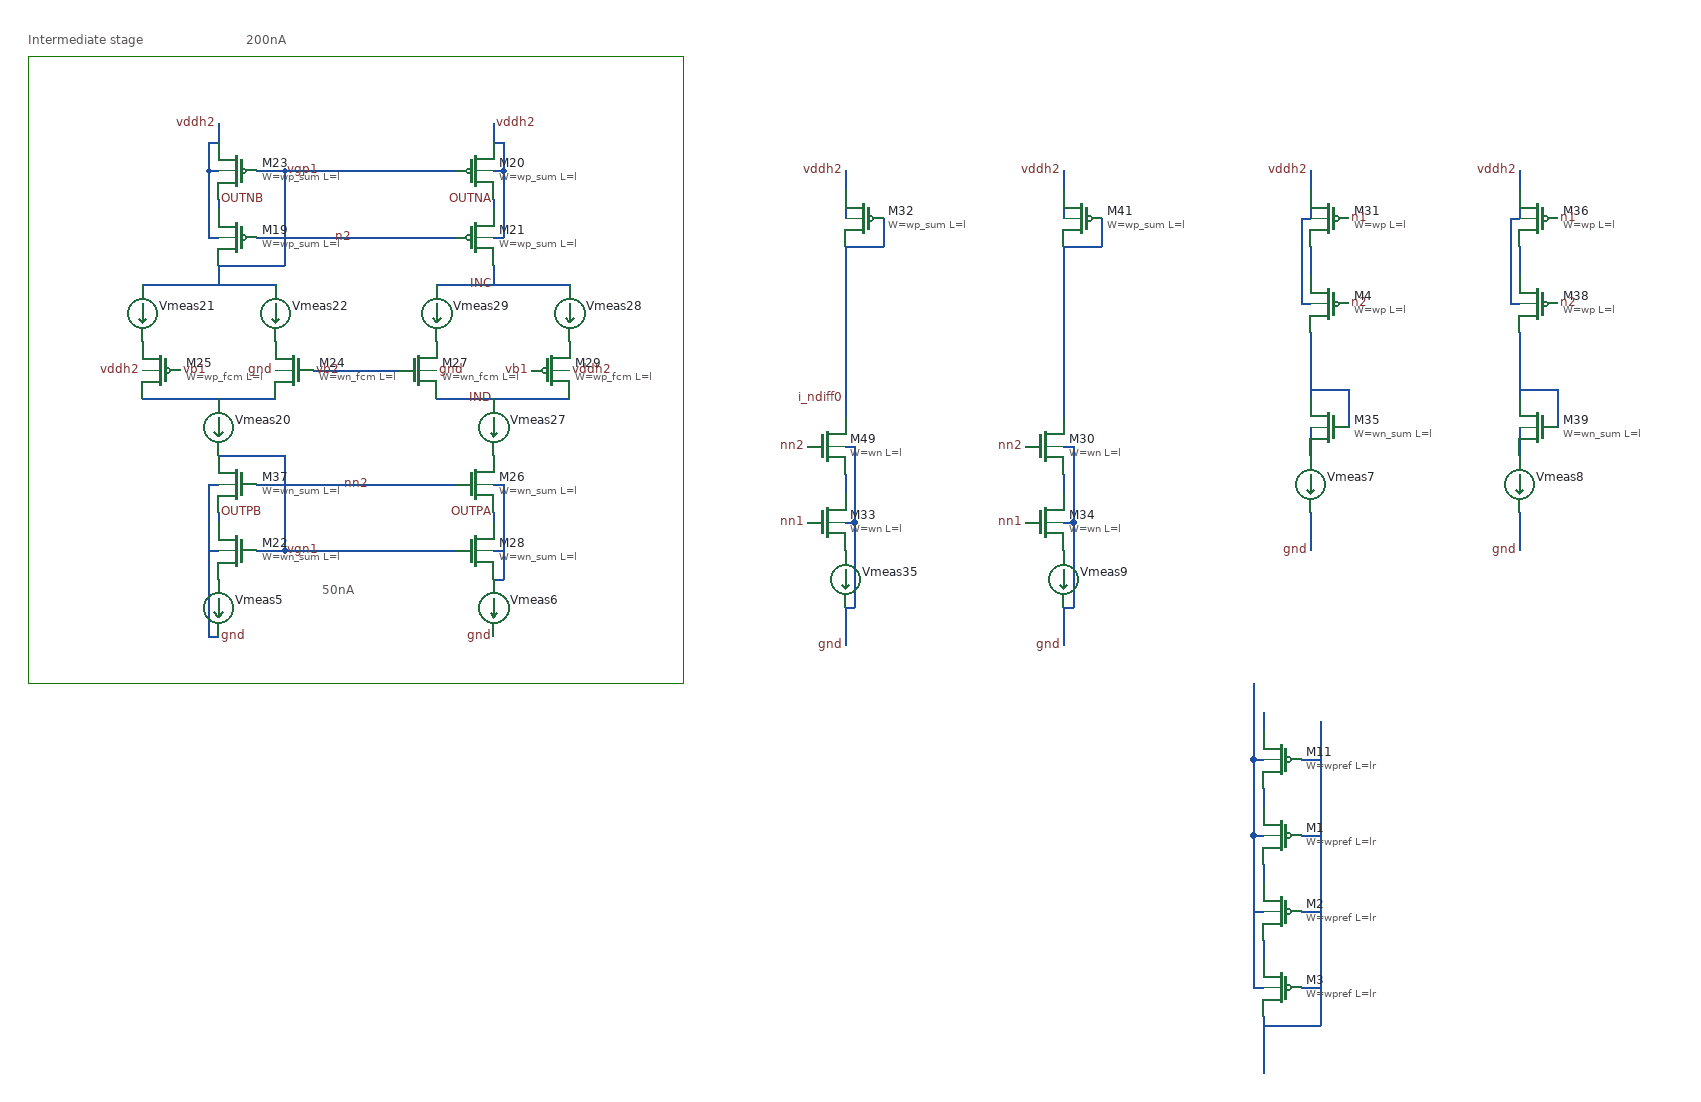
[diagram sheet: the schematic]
v {xschem version=3.4.7 file_version=1.2}
G {}
K {}
V {}
S {}
E {}
B 2 -90 620 710 1020 {flags=graph
y1=4.8e-08
y2=7.8e-08
ypos1=0
ypos2=2
divy=5
subdivy=1
unity=1
x1=1000000
x2=1200000
divx=5
subdivx=1
xlabmag=1.0
ylabmag=1.0
dataset=-1
unitx=1
logx=0
logy=0
color="4 5"
node="i(vmeas21)
i(vmeas22)"}
P 4 5 -230 580 460 580 460 -80 -230 -80 -230 580 {}
T {Intermediate stage} -230 -110 0 0 0.4 0.4 {}
T {50nA} 80 470 0 0 0.4 0.4 {}
T {200nA} 0 -110 0 0 0.4 0.4 {}
N -30 400 -30 410 {lab=OUTPB}
N 10 440 40 440 {lab=vgn1}
N 40 350 40 440 {lab=vgn1}
N 40 340 40 350 {lab=vgn1}
N -30 340 40 340 {lab=vgn1}
N -40 370 -30 370 {lab=gnd}
N -40 370 -40 470 {lab=gnd}
N -40 440 -30 440 {lab=gnd}
N -30 70 -30 80 {lab=OUTNB}
N -30 -10 -30 10 {lab=vddh2}
N 10 40 40 40 {lab=vgp1}
N 40 40 40 50 {lab=vgp1}
N -40 40 -30 40 {lab=vddh2}
N -40 10 -40 40 {lab=vddh2}
N -40 10 -30 10 {lab=vddh2}
N -40 110 -30 110 {lab=vddh2}
N -40 40 -40 110 {lab=vddh2}
N -110 280 30 280 {lab=#net5}
N -110 160 30 160 {lab=vgp1}
N -30 140 40 140 {lab=vgp1}
N -30 140 -30 150 {lab=vgp1}
N -30 150 -30 160 {lab=vgp1}
N 40 50 40 140 {lab=vgp1}
N 260 400 260 410 {lab=OUTPA}
N 190 440 220 440 {lab=vgn1}
N 260 370 270 370 {lab=#net6}
N 270 370 270 470 {lab=#net6}
N 260 470 270 470 {lab=#net6}
N 260 440 270 440 {lab=#net6}
N 260 70 260 80 {lab=OUTNA}
N 260 -10 260 10 {lab=vddh2}
N 190 40 220 40 {lab=vgp1}
N 260 40 270 40 {lab=vddh2}
N 270 10 270 40 {lab=vddh2}
N 260 10 270 10 {lab=vddh2}
N 260 110 270 110 {lab=vddh2}
N 270 40 270 110 {lab=vddh2}
N 200 280 340 280 {lab=IND}
N 200 160 340 160 {lab=INC}
N 260 140 260 150 {lab=INC}
N 260 150 260 160 {lab=INC}
N 40 40 190 40 {lab=vgp1}
N 40 440 190 440 {lab=vgn1}
N 10 370 220 370 {lab=nn2}
N 10 110 220 110 {lab=n2}
N 70 250 160 250 {lab=vb2}
N -40 470 -40 530 {lab=gnd}
N -40 530 -30 530 {lab=gnd}
N 630 500 630 540 {lab=gnd}
N 630 360 630 380 {lab=#net7}
N 630 410 640 410 {lab=gnd}
N 640 410 640 500 {lab=gnd}
N 630 500 640 500 {lab=gnd}
N 630 330 640 330 {lab=gnd}
N 640 330 640 410 {lab=gnd}
N 630 280 630 300 {lab=i_ndiff0}
N 630 120 630 280 {lab=i_ndiff0}
N 630 40 630 60 {lab=vddh2}
N 670 90 670 120 {lab=i_ndiff0}
N 630 120 670 120 {lab=i_ndiff0}
N 630 60 630 90 {lab=vddh2}
N 1120 40 1120 60 {lab=vddh2}
N 1120 60 1120 90 {lab=vddh2}
N 1110 180 1120 180 {lab=vddh2}
N 1110 90 1110 180 {lab=vddh2}
N 1110 90 1120 90 {lab=vddh2}
N 1120 120 1120 150 {lab=#net8}
N 1120 400 1120 440 {lab=gnd}
N 1120 310 1120 340 {lab=#net9}
N 1160 270 1160 310 {lab=#net10}
N 1120 210 1120 280 {lab=#net10}
N 1120 270 1160 270 {lab=#net10}
N 1340 40 1340 60 {lab=vddh2}
N 1340 60 1340 90 {lab=vddh2}
N 1330 180 1340 180 {lab=vddh2}
N 1330 90 1330 180 {lab=vddh2}
N 1330 90 1340 90 {lab=vddh2}
N 1340 120 1340 150 {lab=#net11}
N 1340 400 1340 440 {lab=gnd}
N 1340 310 1340 340 {lab=#net12}
N 1380 270 1380 310 {lab=#net13}
N 1340 210 1340 280 {lab=#net13}
N 1340 270 1380 270 {lab=#net13}
N 860 500 860 540 {lab=gnd}
N 860 360 860 380 {lab=#net14}
N 860 410 870 410 {lab=gnd}
N 870 410 870 500 {lab=gnd}
N 860 500 870 500 {lab=gnd}
N 860 330 870 330 {lab=gnd}
N 870 330 870 410 {lab=gnd}
N 860 280 860 300 {lab=#net15}
N 860 120 860 280 {lab=#net15}
N 860 40 860 60 {lab=vddh2}
N 900 90 900 120 {lab=#net15}
N 860 120 900 120 {lab=#net15}
N 860 60 860 90 {lab=vddh2}
N 1070 610 1070 630 {lab=#net1}
N 1060 660 1070 660 {lab=#net6}
N 1060 580 1060 660 {lab=#net6}
N 1130 620 1130 710 {lab=#net7}
N 1110 660 1130 660 {lab=#net7}
N 1060 740 1070 740 {lab=#net6}
N 1060 660 1060 740 {lab=#net6}
N 1070 690 1070 710 {lab=#net8}
N 1130 710 1130 800 {lab=#net7}
N 1110 740 1130 740 {lab=#net7}
N 1070 770 1070 790 {lab=#net9}
N 1070 850 1070 870 {lab=#net10}
N 1060 900 1070 900 {lab=#net6}
N 1060 740 1060 900 {lab=#net6}
N 1060 820 1070 820 {lab=#net6}
N 1070 930 1070 990 {lab=#net7}
N 1130 800 1130 940 {lab=#net7}
N 1070 940 1130 940 {lab=#net7}
N 1110 820 1130 820 {lab=#net7}
N 1110 900 1130 900 {lab=#net7}
C {devices/lab_pin.sym} -30 530 2 0 {name=p80 sig_type=std_logic lab=gnd}
C {devices/ammeter.sym} -30 310 0 1 {name=Vmeas20 savecurrent=true spice_ignore=0}
C {sky130_fd_pr/pfet_g5v0d10v5.sym} -10 40 0 1 {name=M23
L=l
W=wp_sum
nf=1
mult=m_sum
ad="'int((nf+1)/2) * W/nf * 0.29'" 
pd="'2*int((nf+1)/2) * (W/nf + 0.29)'"
as="'int((nf+2)/2) * W/nf * 0.29'" 
ps="'2*int((nf+2)/2) * (W/nf + 0.29)'"
nrd="'0.29 / W'" nrs="'0.29 / W'"
sa=0 sb=0 sd=0
model=pfet_g5v0d10v5
spiceprefix=X
}
C {devices/lab_pin.sym} -30 -10 0 0 {name=p82 sig_type=std_logic lab=vddh2}
C {sky130_fd_pr/nfet_g5v0d10v5.sym} 50 250 0 1 {name=M24
L=l
W=wn_fcm
nf=1
mult=m_fcm
ad="'int((nf+1)/2) * W/nf * 0.29'" 
pd="'2*int((nf+1)/2) * (W/nf + 0.29)'"
as="'int((nf+2)/2) * W/nf * 0.29'" 
ps="'2*int((nf+2)/2) * (W/nf + 0.29)'"
nrd="'0.29 / W'" nrs="'0.29 / W'"
sa=0 sb=0 sd=0
model=nfet_g5v0d10v5
spiceprefix=X
}
C {devices/ammeter.sym} -110 190 0 0 {name=Vmeas21 savecurrent=true spice_ignore=0}
C {devices/ammeter.sym} 30 190 0 0 {name=Vmeas22 savecurrent=true spice_ignore=0}
C {devices/lab_pin.sym} -70 250 2 0 {name=p84 sig_type=std_logic lab=vb1}
C {devices/lab_pin.sym} 70 250 2 0 {name=p85 sig_type=std_logic lab=vb2}
C {devices/lab_pin.sym} -110 250 0 0 {name=p86 sig_type=std_logic lab=vddh2}
C {devices/lab_pin.sym} 30 250 2 1 {name=p87 sig_type=std_logic lab=gnd}
C {sky130_fd_pr/pfet_g5v0d10v5.sym} -90 250 0 1 {name=M25
L=l
W=wp_fcm
nf=1
mult=m_fcm
ad="'int((nf+1)/2) * W/nf * 0.29'" 
pd="'2*int((nf+1)/2) * (W/nf + 0.29)'"
as="'int((nf+2)/2) * W/nf * 0.29'" 
ps="'2*int((nf+2)/2) * (W/nf + 0.29)'"
nrd="'0.29 / W'" nrs="'0.29 / W'"
sa=0 sb=0 sd=0
model=pfet_g5v0d10v5
spiceprefix=X
}
C {devices/lab_pin.sym} 40 40 2 0 {name=p91 sig_type=std_logic lab=vgp1}
C {devices/lab_pin.sym} 40 440 2 0 {name=p93 sig_type=std_logic lab=vgn1}
C {devices/lab_pin.sym} 260 70 2 1 {name=p102 sig_type=std_logic lab=OUTNA}
C {devices/lab_pin.sym} 260 400 2 1 {name=p103 sig_type=std_logic lab=OUTPA}
C {devices/lab_pin.sym} 260 530 2 1 {name=p104 sig_type=std_logic lab=gnd}
C {devices/ammeter.sym} 260 310 0 0 {name=Vmeas27 savecurrent=true spice_ignore=0}
C {devices/lab_pin.sym} 260 -10 0 1 {name=p105 sig_type=std_logic lab=vddh2}
C {devices/ammeter.sym} 340 190 0 1 {name=Vmeas28 savecurrent=true spice_ignore=0}
C {devices/ammeter.sym} 200 190 0 1 {name=Vmeas29 savecurrent=true spice_ignore=0}
C {devices/lab_pin.sym} 300 250 2 1 {name=p106 sig_type=std_logic lab=vb1}
C {devices/lab_pin.sym} 340 250 0 1 {name=p107 sig_type=std_logic lab=vddh2}
C {devices/lab_pin.sym} 200 250 2 0 {name=p108 sig_type=std_logic lab=gnd}
C {devices/lab_pin.sym} 260 160 0 0 {name=p109 sig_type=std_logic lab=INC}
C {devices/lab_pin.sym} 260 280 0 0 {name=p110 sig_type=std_logic lab=IND}
C {devices/lab_pin.sym} -30 400 2 0 {name=p111 sig_type=std_logic lab=OUTPB}
C {devices/lab_pin.sym} -30 70 2 0 {name=p112 sig_type=std_logic lab=OUTNB}
C {sky130_fd_pr/nfet_g5v0d10v5.sym} -10 370 0 1 {name=M37
L=l
W=wn_sum
nf=1
mult=m_sum
ad="'int((nf+1)/2) * W/nf * 0.29'" 
pd="'2*int((nf+1)/2) * (W/nf + 0.29)'"
as="'int((nf+2)/2) * W/nf * 0.29'" 
ps="'2*int((nf+2)/2) * (W/nf + 0.29)'"
nrd="'0.29 / W'" nrs="'0.29 / W'"
sa=0 sb=0 sd=0
model=nfet_g5v0d10v5
spiceprefix=X
}
C {devices/lab_pin.sym} 90 110 0 1 {name=p31 sig_type=std_logic lab=n2}
C {devices/lab_pin.sym} 100 370 0 1 {name=p32 sig_type=std_logic lab=nn2}
C {devices/ammeter.sym} -30 500 0 1 {name=Vmeas5 savecurrent=true spice_ignore=0}
C {devices/ammeter.sym} 260 500 0 0 {name=Vmeas6 savecurrent=true spice_ignore=0}
C {sky130_fd_pr/pfet_g5v0d10v5.sym} -10 110 0 1 {name=M19
L=l
W=wp_sum
nf=1
mult=m_sum
ad="'int((nf+1)/2) * W/nf * 0.29'" 
pd="'2*int((nf+1)/2) * (W/nf + 0.29)'"
as="'int((nf+2)/2) * W/nf * 0.29'" 
ps="'2*int((nf+2)/2) * (W/nf + 0.29)'"
nrd="'0.29 / W'" nrs="'0.29 / W'"
sa=0 sb=0 sd=0
model=pfet_g5v0d10v5
spiceprefix=X
}
C {sky130_fd_pr/pfet_g5v0d10v5.sym} 240 40 0 0 {name=M20
L=l
W=wp_sum
nf=1
mult=m_sum
ad="'int((nf+1)/2) * W/nf * 0.29'" 
pd="'2*int((nf+1)/2) * (W/nf + 0.29)'"
as="'int((nf+2)/2) * W/nf * 0.29'" 
ps="'2*int((nf+2)/2) * (W/nf + 0.29)'"
nrd="'0.29 / W'" nrs="'0.29 / W'"
sa=0 sb=0 sd=0
model=pfet_g5v0d10v5
spiceprefix=X
}
C {sky130_fd_pr/pfet_g5v0d10v5.sym} 240 110 0 0 {name=M21
L=l
W=wp_sum
nf=1
mult=m_sum
ad="'int((nf+1)/2) * W/nf * 0.29'" 
pd="'2*int((nf+1)/2) * (W/nf + 0.29)'"
as="'int((nf+2)/2) * W/nf * 0.29'" 
ps="'2*int((nf+2)/2) * (W/nf + 0.29)'"
nrd="'0.29 / W'" nrs="'0.29 / W'"
sa=0 sb=0 sd=0
model=pfet_g5v0d10v5
spiceprefix=X
}
C {sky130_fd_pr/nfet_g5v0d10v5.sym} -10 440 0 1 {name=M22
L=l
W=wn_sum
nf=1
mult=m_sum
ad="'int((nf+1)/2) * W/nf * 0.29'" 
pd="'2*int((nf+1)/2) * (W/nf + 0.29)'"
as="'int((nf+2)/2) * W/nf * 0.29'" 
ps="'2*int((nf+2)/2) * (W/nf + 0.29)'"
nrd="'0.29 / W'" nrs="'0.29 / W'"
sa=0 sb=0 sd=0
model=nfet_g5v0d10v5
spiceprefix=X
}
C {sky130_fd_pr/nfet_g5v0d10v5.sym} 240 370 0 0 {name=M26
L=l
W=wn_sum
nf=1
mult=m_sum
ad="'int((nf+1)/2) * W/nf * 0.29'" 
pd="'2*int((nf+1)/2) * (W/nf + 0.29)'"
as="'int((nf+2)/2) * W/nf * 0.29'" 
ps="'2*int((nf+2)/2) * (W/nf + 0.29)'"
nrd="'0.29 / W'" nrs="'0.29 / W'"
sa=0 sb=0 sd=0
model=nfet_g5v0d10v5
spiceprefix=X
}
C {sky130_fd_pr/nfet_g5v0d10v5.sym} 610 330 0 0 {name=M49
L=l
W=wn
nf=1
mult=\{mdiff0*8\}
ad="'int((nf+1)/2) * W/nf * 0.29'" 
pd="'2*int((nf+1)/2) * (W/nf + 0.29)'"
as="'int((nf+2)/2) * W/nf * 0.29'" 
ps="'2*int((nf+2)/2) * (W/nf + 0.29)'"
nrd="'0.29 / W'" nrs="'0.29 / W'"
sa=0 sb=0 sd=0
model=nfet_g5v0d10v5
spiceprefix=X
}
C {devices/ammeter.sym} 630 470 0 0 {name=Vmeas35 savecurrent=true spice_ignore=0}
C {devices/lab_pin.sym} 630 540 0 0 {name=p140 sig_type=std_logic lab=gnd}
C {devices/lab_pin.sym} 590 410 0 0 {name=p141 sig_type=std_logic lab=nn1}
C {devices/lab_pin.sym} 590 330 0 0 {name=p142 sig_type=std_logic lab=nn2}
C {devices/lab_pin.sym} 630 280 0 0 {name=p176 sig_type=std_logic lab=i_ndiff0}
C {sky130_fd_pr/pfet_g5v0d10v5.sym} 650 90 0 1 {name=M32
L=l
W=wp_sum
nf=1
mult=m_sum
ad="'int((nf+1)/2) * W/nf * 0.29'" 
pd="'2*int((nf+1)/2) * (W/nf + 0.29)'"
as="'int((nf+2)/2) * W/nf * 0.29'" 
ps="'2*int((nf+2)/2) * (W/nf + 0.29)'"
nrd="'0.29 / W'" nrs="'0.29 / W'"
sa=0 sb=0 sd=0
model=pfet_g5v0d10v5
spiceprefix=X
}
C {devices/lab_pin.sym} 630 40 0 0 {name=p27 sig_type=std_logic lab=vddh2}
C {sky130_fd_pr/nfet_g5v0d10v5.sym} 240 440 0 0 {name=M28
L=l
W=wn_sum
nf=1
mult=m_sum
ad="'int((nf+1)/2) * W/nf * 0.29'" 
pd="'2*int((nf+1)/2) * (W/nf + 0.29)'"
as="'int((nf+2)/2) * W/nf * 0.29'" 
ps="'2*int((nf+2)/2) * (W/nf + 0.29)'"
nrd="'0.29 / W'" nrs="'0.29 / W'"
sa=0 sb=0 sd=0
model=nfet_g5v0d10v5
spiceprefix=X
}
C {sky130_fd_pr/pfet_g5v0d10v5.sym} 1140 90 0 1 {name=M31
L=l
W=wp
nf=1
mult=mdiff0
ad="'int((nf+1)/2) * W/nf * 0.29'" 
pd="'2*int((nf+1)/2) * (W/nf + 0.29)'"
as="'int((nf+2)/2) * W/nf * 0.29'" 
ps="'2*int((nf+2)/2) * (W/nf + 0.29)'"
nrd="'0.29 / W'" nrs="'0.29 / W'"
sa=0 sb=0 sd=0
model=pfet_g5v0d10v5
spiceprefix=X
}
C {devices/lab_pin.sym} 1120 40 0 0 {name=p26 sig_type=std_logic lab=vddh2}
C {sky130_fd_pr/nfet_g5v0d10v5.sym} 1140 310 0 1 {name=M35
L=l
W=wn_sum
nf=1
mult=m_sum
ad="'int((nf+1)/2) * W/nf * 0.29'" 
pd="'2*int((nf+1)/2) * (W/nf + 0.29)'"
as="'int((nf+2)/2) * W/nf * 0.29'" 
ps="'2*int((nf+2)/2) * (W/nf + 0.29)'"
nrd="'0.29 / W'" nrs="'0.29 / W'"
sa=0 sb=0 sd=0
model=nfet_g5v0d10v5
spiceprefix=X
}
C {devices/ammeter.sym} 1120 370 0 0 {name=Vmeas7 savecurrent=true spice_ignore=0}
C {devices/lab_pin.sym} 1120 440 0 0 {name=p28 sig_type=std_logic lab=gnd}
C {devices/lab_pin.sym} 1160 90 0 1 {name=p29 sig_type=std_logic lab=n1}
C {devices/lab_pin.sym} 1160 180 0 1 {name=p30 sig_type=std_logic lab=n2}
C {sky130_fd_pr/nfet_g5v0d10v5.sym} 610 410 0 0 {name=M33
L=l
W=wn
nf=1
mult=\{mdiff0*8\}
ad="'int((nf+1)/2) * W/nf * 0.29'" 
pd="'2*int((nf+1)/2) * (W/nf + 0.29)'"
as="'int((nf+2)/2) * W/nf * 0.29'" 
ps="'2*int((nf+2)/2) * (W/nf + 0.29)'"
nrd="'0.29 / W'" nrs="'0.29 / W'"
sa=0 sb=0 sd=0
model=nfet_g5v0d10v5
spiceprefix=X
}
C {sky130_fd_pr/pfet_g5v0d10v5.sym} 1360 90 0 1 {name=M36
L=l
W=wp
nf=1
mult=\{mdiff0*8\}
ad="'int((nf+1)/2) * W/nf * 0.29'" 
pd="'2*int((nf+1)/2) * (W/nf + 0.29)'"
as="'int((nf+2)/2) * W/nf * 0.29'" 
ps="'2*int((nf+2)/2) * (W/nf + 0.29)'"
nrd="'0.29 / W'" nrs="'0.29 / W'"
sa=0 sb=0 sd=0
model=pfet_g5v0d10v5
spiceprefix=X
}
C {sky130_fd_pr/pfet_g5v0d10v5.sym} 1360 180 0 1 {name=M38
L=l
W=wp
nf=1
mult=\{mdiff0*8\}
ad="'int((nf+1)/2) * W/nf * 0.29'" 
pd="'2*int((nf+1)/2) * (W/nf + 0.29)'"
as="'int((nf+2)/2) * W/nf * 0.29'" 
ps="'2*int((nf+2)/2) * (W/nf + 0.29)'"
nrd="'0.29 / W'" nrs="'0.29 / W'"
sa=0 sb=0 sd=0
model=pfet_g5v0d10v5
spiceprefix=X
}
C {devices/lab_pin.sym} 1340 40 0 0 {name=p33 sig_type=std_logic lab=vddh2}
C {sky130_fd_pr/nfet_g5v0d10v5.sym} 1360 310 0 1 {name=M39
L=l
W=wn_sum
nf=1
mult=m_sum
ad="'int((nf+1)/2) * W/nf * 0.29'" 
pd="'2*int((nf+1)/2) * (W/nf + 0.29)'"
as="'int((nf+2)/2) * W/nf * 0.29'" 
ps="'2*int((nf+2)/2) * (W/nf + 0.29)'"
nrd="'0.29 / W'" nrs="'0.29 / W'"
sa=0 sb=0 sd=0
model=nfet_g5v0d10v5
spiceprefix=X
}
C {devices/ammeter.sym} 1340 370 0 0 {name=Vmeas8 savecurrent=true spice_ignore=0}
C {devices/lab_pin.sym} 1340 440 0 0 {name=p34 sig_type=std_logic lab=gnd}
C {devices/lab_pin.sym} 1380 90 0 1 {name=p35 sig_type=std_logic lab=n1}
C {devices/lab_pin.sym} 1380 180 0 1 {name=p36 sig_type=std_logic lab=n2}
C {devices/ammeter.sym} 860 470 0 0 {name=Vmeas9 savecurrent=true spice_ignore=0}
C {devices/lab_pin.sym} 860 540 0 0 {name=p37 sig_type=std_logic lab=gnd}
C {devices/lab_pin.sym} 820 410 0 0 {name=p38 sig_type=std_logic lab=nn1}
C {devices/lab_pin.sym} 820 330 0 0 {name=p39 sig_type=std_logic lab=nn2}
C {sky130_fd_pr/pfet_g5v0d10v5.sym} 880 90 0 1 {name=M41
L=l
W=wp_sum
nf=1
mult=m_sum
ad="'int((nf+1)/2) * W/nf * 0.29'" 
pd="'2*int((nf+1)/2) * (W/nf + 0.29)'"
as="'int((nf+2)/2) * W/nf * 0.29'" 
ps="'2*int((nf+2)/2) * (W/nf + 0.29)'"
nrd="'0.29 / W'" nrs="'0.29 / W'"
sa=0 sb=0 sd=0
model=pfet_g5v0d10v5
spiceprefix=X
}
C {devices/lab_pin.sym} 860 40 0 0 {name=p41 sig_type=std_logic lab=vddh2}
C {sky130_fd_pr/nfet_g5v0d10v5.sym} 840 330 0 0 {name=M30
L=l
W=wn
nf=1
mult=mdiff0
ad="'int((nf+1)/2) * W/nf * 0.29'" 
pd="'2*int((nf+1)/2) * (W/nf + 0.29)'"
as="'int((nf+2)/2) * W/nf * 0.29'" 
ps="'2*int((nf+2)/2) * (W/nf + 0.29)'"
nrd="'0.29 / W'" nrs="'0.29 / W'"
sa=0 sb=0 sd=0
model=nfet_g5v0d10v5
spiceprefix=X
}
C {sky130_fd_pr/nfet_g5v0d10v5.sym} 840 410 0 0 {name=M34
L=l
W=wn
nf=1
mult=mdiff0
ad="'int((nf+1)/2) * W/nf * 0.29'" 
pd="'2*int((nf+1)/2) * (W/nf + 0.29)'"
as="'int((nf+2)/2) * W/nf * 0.29'" 
ps="'2*int((nf+2)/2) * (W/nf + 0.29)'"
nrd="'0.29 / W'" nrs="'0.29 / W'"
sa=0 sb=0 sd=0
model=nfet_g5v0d10v5
spiceprefix=X
}
C {sky130_fd_pr/pfet_g5v0d10v5.sym} 1140 180 0 1 {name=M4
L=l
W=wp
nf=1
mult=mdiff0
ad="'int((nf+1)/2) * W/nf * 0.29'" 
pd="'2*int((nf+1)/2) * (W/nf + 0.29)'"
as="'int((nf+2)/2) * W/nf * 0.29'" 
ps="'2*int((nf+2)/2) * (W/nf + 0.29)'"
nrd="'0.29 / W'" nrs="'0.29 / W'"
sa=0 sb=0 sd=0
model=pfet_g5v0d10v5
spiceprefix=X
}
C {sky130_fd_pr/pfet_g5v0d10v5.sym} 320 250 0 0 {name=M29
L=l
W=wp_fcm
nf=1
mult=m_fcm
ad="'int((nf+1)/2) * W/nf * 0.29'" 
pd="'2*int((nf+1)/2) * (W/nf + 0.29)'"
as="'int((nf+2)/2) * W/nf * 0.29'" 
ps="'2*int((nf+2)/2) * (W/nf + 0.29)'"
nrd="'0.29 / W'" nrs="'0.29 / W'"
sa=0 sb=0 sd=0
model=pfet_g5v0d10v5
spiceprefix=X
}
C {sky130_fd_pr/nfet_g5v0d10v5.sym} 180 250 0 0 {name=M27
L=l
W=wn_fcm
nf=1
mult=m_fcm
ad="'int((nf+1)/2) * W/nf * 0.29'" 
pd="'2*int((nf+1)/2) * (W/nf + 0.29)'"
as="'int((nf+2)/2) * W/nf * 0.29'" 
ps="'2*int((nf+2)/2) * (W/nf + 0.29)'"
nrd="'0.29 / W'" nrs="'0.29 / W'"
sa=0 sb=0 sd=0
model=nfet_g5v0d10v5
spiceprefix=X
}
C {sky130_fd_pr/pfet_g5v0d10v5.sym} 1090 660 0 1 {name=M11
L=lr
W=wpref
nf=1
mult=2
ad="'int((nf+1)/2) * W/nf * 0.29'" 
pd="'2*int((nf+1)/2) * (W/nf + 0.29)'"
as="'int((nf+2)/2) * W/nf * 0.29'" 
ps="'2*int((nf+2)/2) * (W/nf + 0.29)'"
nrd="'0.29 / W'" nrs="'0.29 / W'"
sa=0 sb=0 sd=0
model=pfet_g5v0d10v5
spiceprefix=X
}
C {sky130_fd_pr/pfet_g5v0d10v5.sym} 1090 740 0 1 {name=M1
L=lr
W=wpref
nf=1
mult=2
ad="'int((nf+1)/2) * W/nf * 0.29'" 
pd="'2*int((nf+1)/2) * (W/nf + 0.29)'"
as="'int((nf+2)/2) * W/nf * 0.29'" 
ps="'2*int((nf+2)/2) * (W/nf + 0.29)'"
nrd="'0.29 / W'" nrs="'0.29 / W'"
sa=0 sb=0 sd=0
model=pfet_g5v0d10v5
spiceprefix=X
}
C {sky130_fd_pr/pfet_g5v0d10v5.sym} 1090 820 0 1 {name=M2
L=lr
W=wpref
nf=1
mult=2
ad="'int((nf+1)/2) * W/nf * 0.29'" 
pd="'2*int((nf+1)/2) * (W/nf + 0.29)'"
as="'int((nf+2)/2) * W/nf * 0.29'" 
ps="'2*int((nf+2)/2) * (W/nf + 0.29)'"
nrd="'0.29 / W'" nrs="'0.29 / W'"
sa=0 sb=0 sd=0
model=pfet_g5v0d10v5
spiceprefix=X
}
C {sky130_fd_pr/pfet_g5v0d10v5.sym} 1090 900 0 1 {name=M3
L=lr
W=wpref
nf=1
mult=2
ad="'int((nf+1)/2) * W/nf * 0.29'" 
pd="'2*int((nf+1)/2) * (W/nf + 0.29)'"
as="'int((nf+2)/2) * W/nf * 0.29'" 
ps="'2*int((nf+2)/2) * (W/nf + 0.29)'"
nrd="'0.29 / W'" nrs="'0.29 / W'"
sa=0 sb=0 sd=0
model=pfet_g5v0d10v5
spiceprefix=X
}
